! (c) 2009  Infineon Technologies AG, Munich
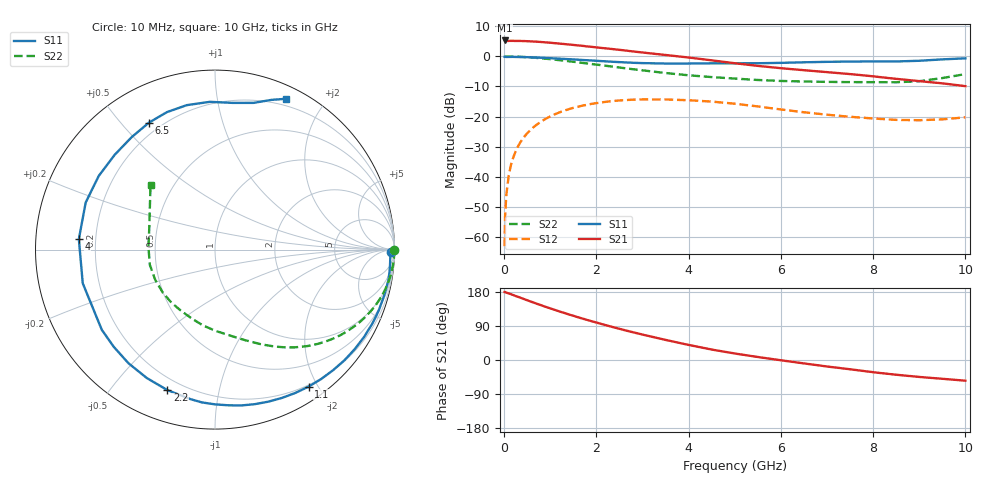
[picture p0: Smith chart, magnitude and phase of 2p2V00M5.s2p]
! Infineon Technologies  Discrete & RF Semiconductors
! BFP420
! VCE =  2.0 V,  IC =  0.5 mA
! Common Emitter S-Parameters:  Nov 2009
# GHz  S  MA  R  50
!  f  S11  S21  S12  S22
! GHz  MAG  ANG  MAG  ANG  MAG  ANG  MAG  ANG
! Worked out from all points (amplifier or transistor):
!   46 points, 10 MHz to 10 GHz, reference 50 ohm
!   highest |S21| = 5.3 dB at 10 MHz (marker M1)
!   |S21| within 3 dB of that: start of sweep to 2.424 GHz
!   unconditionally stable (mu >= 1): 4.408 GHz to end of sweep
!   at 300 MHz: K = 0.02, MSG = 17.5 dB, |S12| = -30.0 dB
!   at 1.7 GHz: K = 0.28, MSG = 9.9 dB, |S12| = -16.4 dB
!   at 10 GHz: K = 1.61, MAG = 0.6 dB, |S12| = -20.3 dB
!   lowest NFmin = 0.68 dB at 900 MHz
!   S11 on the Smith chart (normalised r, x): 10 MHz: 70, -55; 1.1 GHz: 0.18, -1.88; 2.2 GHz: 0.14, -0.71; 4 GHz: 0.14, +0.04; 6.5 GHz: 0.15, +0.60; 10 GHz: 0.13, +1.57
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0.01  0.9825 -0.8  1.839 179.5  0.0007 71.9  0.9987 -0.1
0.02  0.9823 -1.0  1.787 179.5  0.0022 87.1  0.9985 -0.5
0.05  0.9776 -2.5  1.798 177.7  0.0052 89.3  0.9986 -1.4
0.1  0.9791 -5.1  1.809 175.7  0.0106 87.1  0.9979 -2.9
0.2  0.981 -10.1  1.811 171.2  0.0211 83.7  0.9939 -5.8
0.35  0.974 -17.7  1.805 164.5  0.0371 79.0  0.9841 -10.1
0.5  0.9685 -25.3  1.788 157.7  0.0527 74.0  0.9694 -14.3
0.8  0.9489 -40.5  1.733 144.6  0.0823 64.1  0.9294 -22.2
1.1  0.9245 -55.7  1.658 132.2  0.109 54.5  0.8814 -29.5
1.4  0.8978 -70.7  1.576 120.3  0.1324 45.2  0.8301 -36.3
1.7  0.8704 -85.2  1.495 109.3  0.1518 36.5  0.7789 -42.3
2.2  0.8266 -108.7  1.36 92.0  0.1755 22.8  0.6982 -51.3
2.8  0.782 -136.2  1.207 73.0  0.1906 7.5  0.611 -61.0
3.5  0.7604 -165.7  1.054 53.0  0.1921 -8.2  0.5289 -72.1
4  0.7608 175.6  0.957 39.8  0.1867 -17.5  0.4847 -80.4
4.5  0.7667 160.0  0.859 27.6  0.1771 -26.1  0.4525 -89.7
5.5  0.7691 136.5  0.695 7.9  0.1472 -39.1  0.4052 -108.6
6.5  0.7973 117.5  0.589 -9.0  0.1178 -44.3  0.3826 -129.3
7  0.8114 109.3  0.547 -17.1  0.1072 -44.1  0.3767 -140.5
8.5  0.8233 83.1  0.423 -38.9  0.088 -37.2  0.3711 177.8
9  0.8451 75.3  0.388 -44.7  0.0868 -32.2  0.3866 161.2
10  0.9276 64.9  0.32 -54.6  0.097 -24.3  0.508 135.0
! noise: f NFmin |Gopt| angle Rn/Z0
0.9  0.68  0.78  35  0.65
1.8  1.42  0.6  75  0.5
2.4  1.57  0.58  98  0.37
3  2.1  0.58  128  0.24
4  2.49  0.57  177  0.09
